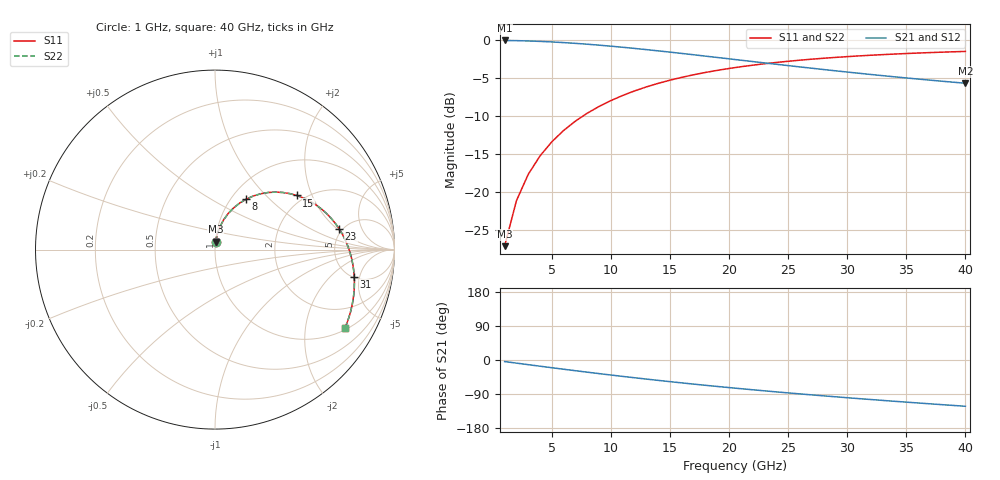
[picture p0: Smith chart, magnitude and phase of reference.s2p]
! circuitRF F0 spike reference -- case A, openEMS, PEC wire of true radius 12.7 um, dw 6.35 um
! openEMS probes -> S by postproc.py (own time column per probe); port 1 excited only;
! S22 = S11 and S12 = S21 by the mirror symmetry of the geometry (not a second run)
# GHz S RI R 50
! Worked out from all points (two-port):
!   40 points, 1 GHz to 40 GHz, reference 50 ohm
!   highest |S21| = -0.01 dB at 1 GHz (marker M1); lowest = -5.7 dB at 40 GHz (marker M2)
!   |S21| within 3 dB of the highest: start of sweep to 23.21 GHz
!   lowest |S11| = -27.1 dB at 1 GHz (marker M3), VSWR 1.09, Z = 50.1 + j4.4 ohm
!   |S11| at or under -10 dB: start of sweep to 7.616 GHz
!   |S22| runs from -27.1 to -1.5 dB; largest |S21 - S12| = 0
!   S11 on the Smith chart (normalised r, x): 1 GHz: 1.00, +0.09; 8 GHz: 1.17, +0.74; 15 GHz: 1.81, +1.56; 23 GHz: 4.69, +2.13; 31 GHz: 5.16, -4.12; 40 GHz: 1.07, -3.27
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1  0.00311 0.0438  0.9964 -0.0718  0.9964 -0.0718  0.00311 0.0438
2  0.0124 0.0867  0.9858 -0.1425  0.9858 -0.1425  0.0124 0.0867
3  0.0276 0.1278  0.9686 -0.2115  0.9686 -0.2115  0.0276 0.1278
4  0.0483 0.1663  0.9449 -0.2777  0.9449 -0.2777  0.0483 0.1663
5  0.074 0.2014  0.9155 -0.3404  0.9155 -0.3404  0.074 0.2014
6  0.1041 0.2326  0.8808 -0.3989  0.8808 -0.3989  0.1041 0.2326
7  0.1378 0.2594  0.8417 -0.4529  0.8417 -0.4529  0.1378 0.2594
8  0.1744 0.2814  0.7988 -0.5019  0.7988 -0.5019  0.1744 0.2814
9  0.2133 0.2986  0.753 -0.5458  0.753 -0.5458  0.2133 0.2986
11  0.2947 0.318  0.6555 -0.6178  0.6555 -0.6178  0.2947 0.318
12  0.336 0.3204  0.605 -0.6461  0.605 -0.6461  0.336 0.3204
14  0.417 0.3119  0.5037 -0.6883  0.5037 -0.6883  0.417 0.3119
15  0.4558 0.3015  0.4538 -0.7028  0.4538 -0.7028  0.4558 0.3015
18  0.5615 0.2498  0.3109 -0.7235  0.3109 -0.7235  0.5615 0.2498
21  0.647 0.1745  0.1825 -0.7173  0.1825 -0.7173  0.647 0.1745
23  0.6917 0.1155  0.1063 -0.7022  0.1063 -0.7022  0.6917 0.1155
25  0.7265 0.052  0.0378 -0.6808  0.0378 -0.6808  0.7265 0.052
27  0.7517 -0.0144  -0.0234 -0.6547  -0.0234 -0.6547  0.7517 -0.0144
31  0.7757 -0.1499  -0.1256 -0.5937  -0.1256 -0.5937  0.7757 -0.1499
34  0.7732 -0.2501  -0.1867 -0.544  -0.1867 -0.544  0.7732 -0.2501
37  0.7553 -0.3462  -0.2366 -0.493  -0.2366 -0.493  0.7553 -0.3462
40  0.7242 -0.4365  -0.277 -0.4421  -0.277 -0.4421  0.7242 -0.4365
